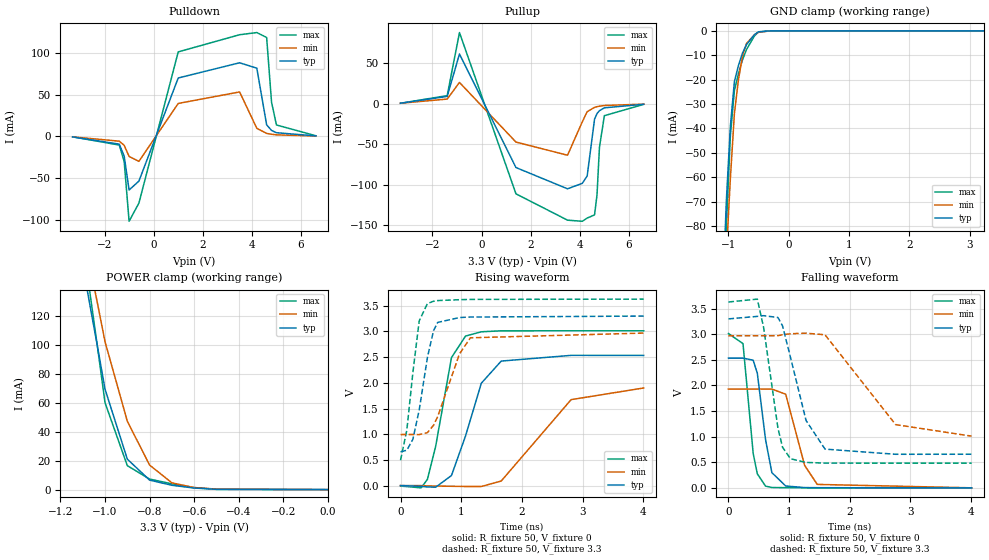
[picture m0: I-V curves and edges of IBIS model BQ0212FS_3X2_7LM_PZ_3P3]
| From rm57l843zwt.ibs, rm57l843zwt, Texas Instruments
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|   Model Cell FS_3X2_7LM_PZ_3P3
|BQ0212FS_3X2_7LM_PZ_3P3
[Model]   BQ0212FS_3X2_7LM_PZ_3P3
Model_type   I/O
Polarity   Non-Inverting
Enable   Active-Low
Vinl =  1.25
Vinh =  1.65
Cref =  15.0001pF
Rref =  101.0000M
Vref =  0V
Vmeas =  1.65
C_comp   1.2p   1.2p   1.2p
[Model Spec]
Vinl   1.25   1.12   1.38
Vinh   1.65   1.45   1.75
[Temperature Range]   25   155   -40
[Voltage Range]   3.3   2.97   3.63
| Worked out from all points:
|   slope of the pulldown table from 0 to 0.495 V, typ, clamps not added: 11.9 ohm
|   slope of the pullup table from 0 to 0.495 V, typ, clamps not added: 14.3 ohm
|   GND clamp passes 1 mA (typ) near -0.53 V on its own axis
|   POWER clamp passes 1 mA (typ) near -0.59 V on its own axis
|   rising waveform, R_fixture 50, V_fixture 0: 20-80 % time 399ps typ, 714ps min, 274ps max; typ from 0 V to 2.53 V
|   rising waveform, R_fixture 50, V_fixture 3.3: 20-80 % time 224ps typ, 347ps min, 171ps max; typ from 0.656 V to 3.3 V
|   falling waveform, R_fixture 50, V_fixture 0: 20-80 % time 170ps typ, 242ps min, 138ps max; typ from 2.53 V to 0 V
|   falling waveform, R_fixture 50, V_fixture 3.3: 20-80 % time 342ps typ, 655ps min, 230ps max; typ from 3.3 V to 0.657 V
[POWER_clamp]
|   voltage   I(typ)   I(min)   I(max)
-3.3V     2.375A     2.63A      3.153A
-1.1V     156mA      180.2mA    173.4mA
-1.067V   127.2mA    154.3mA    135.6mA
-1.033V   98.41mA    128.4mA    97.92mA
-1V       69.61mA    102.5mA    60.2mA
-900mV    21.12mA    47.41mA    16.6mA
-800mV    6.574mA    17mA       7.307mA
-700mV    2.998mA    4.687mA    3.989mA
-600mV    1.086mA    1.404mA    1.425mA
-500mV    187uA      358uA      203.4uA
0V        311.4pA    5.945nA    272.3pA
[Pulldown]
|   voltage   I(typ)   I(min)   I(max)
-3.3V     -554.3uA   -511.5uA   -526.2uA
-1.4V     -9.291mA   -5.703mA   -10.34mA
-1.2V     -23.68mA   -10.64mA   -30.19mA
-1V       -64.35mA   -24mA      -101.9mA
-600mV    -53.61mA   -29.92mA   -79.98mA
1V        70.16mA    39.6mA     101.5mA
3.5V      88.44mA    53.42mA    122.1mA
4.2V      81.93mA    9.711mA    124.7mA
4.6V      13.96mA    3.646mA    118.8mA
4.8V      7.183mA    2.57mA     41.14mA
5V        4.453mA    1.905mA    13.75mA
6.6V      621.1uA    479.2uA    840.9uA
[Pullup]
|   voltage   I(typ)   I(min)   I(max)
-3.3V     614.6uA    591.9uA    551.1uA
-1.4V     9.028mA    5.738mA    10.01mA
-900mV    61.32mA    26.24mA    87.8mA
1.4V      -78.76mA   -47.33mA   -111.2mA
3.5V      -105mA     -63.56mA   -143.7mA
4.1V      -98.29mA   -22.39mA   -145.1mA
4.3V      -89.13mA   -9.839mA   -141.1mA
4.6V      -19.02mA   -4.469mA   -137.2mA
4.7V      -12.15mA   -3.653mA   -112.5mA
4.8V      -8.616mA   -3.042mA   -53.65mA
5V        -5.089mA   -2.205mA   -14.76mA
6.6V      -663.5uA   -536.5uA   -825.6uA
[GND_clamp]
|   voltage   I(typ)   I(min)   I(max)
-3.3V     -1.947A    -1.623A    -3.254A
-1.1V     -112mA     -127mA     -135.8mA
-1.033V   -69.61mA   -91.63mA   -80.19mA
-966.7mV  -39.23mA   -60.62mA   -43.11mA
-900mV    -20.86mA   -34.02mA   -24.52mA
-833.3mV  -14.26mA   -20.12mA   -17.61mA
-766.7mV  -9.192mA   -10.52mA   -12mA
-700mV    -5.665mA   -5.207mA   -7.702mA
-566.7mV  -1.565mA   -1.572mA   -2.054mA
-500mV    -402.1uA   -585.5uA   -459.6uA
-300mV    -821.9nA   -7.168uA   -404.6nA
3.233V    296.5pA    4.008uA    206.9pA
[Ramp]
| variable   typ   min   max
dV/dt_f   1.632017/0.3487468n   1.217274/0.676831n   1.942304/0.2338723n
dV/dt_r   1.540068/0.4015431n   1.170106/0.7431858n   1.835653/0.2780119n
R_load = 50
[Rising Waveform]
R_fixture = 50
V_fixture = 0
V_fixture_min = 0
V_fixture_max = 0
|   time   V(typ)   V(min)   V(max)
0s        300.3uV    -965.4nV   -9.822mV
340ps     -15.63mV   -290.7uV   -44.89mV
444ps     -27.36mV   -6.964mV   122.8mV
580ps     -31.81mV   -9.755mV   768.7mV
840ps     195.6mV    -13.95mV   2.492V
1.072ns   967.2mV    -18.2mV    2.911V
1.332ns   1.993V     -18.33mV   2.994V
1.66ns    2.424V     88.3mV     3.013V
2.812ns   2.535V     1.673V     3.014V
4.008ns   2.534V     1.9V       3.014V
[Rising Waveform]
R_fixture = 50
V_fixture = 3.3
V_fixture_min = 2.97
V_fixture_max = 3.63
|   time   V(typ)   V(min)   V(max)
0s        656.3mV    993.4mV    492.9mV
104ps     688mV      993.4mV    1.08V
204ps     901.4mV    993.5mV    2.203V
308ps     1.471V     992.1mV    3.207V
444ps     2.499V     1.03V      3.544V
544ps     3.015V     1.174V     3.589V
612ps     3.176V     1.34V      3.602V
972ps     3.272V     2.564V     3.619V
1.152ns   3.281V     2.877V     3.625V
4.008ns   3.3V       2.969V     3.63V
[Falling Waveform]
R_fixture = 50
V_fixture = 0
V_fixture_min = 0
V_fixture_max = 0
|   time   V(typ)   V(min)   V(max)
0s        2.534V     1.93V      3.014V
240ps     2.534V     1.93V      2.817V
408ps     2.493V     1.93V      671.4mV
476ps     2.238V     1.93V      274.9mV
612ps     939.9mV    1.93V      33.62mV
716ps     297.4mV    1.93V      7.303mV
944ps     36.39mV    1.829V     3.346mV
1.256ns   5.523mV    438.6mV    1.066mV
1.464ns   3.167mV    67.28mV    658uV
4.008ns   97.17uV    784.4uV    -1.881uV
[Falling Waveform]
R_fixture = 50
V_fixture = 3.3
V_fixture_min = 2.97
V_fixture_max = 3.63
|   time   V(typ)   V(min)   V(max)
0s        3.3V       2.97V      3.63V
476ps     3.349V     2.97V      3.686V
580ps     3.363V     2.97V      3.131V
816ps     3.327V     2.972V     1.165V
892ps     3.162V     2.99V      792.4mV
1.024ns   2.543V     3.01V      567.5mV
1.28ns    1.314V     3.021V     497mV
1.592ns   756.9mV    2.99V      483.4mV
2.756ns   655.8mV    1.235V     482.5mV
4.008ns   656.6mV    1.01V      482.2mV
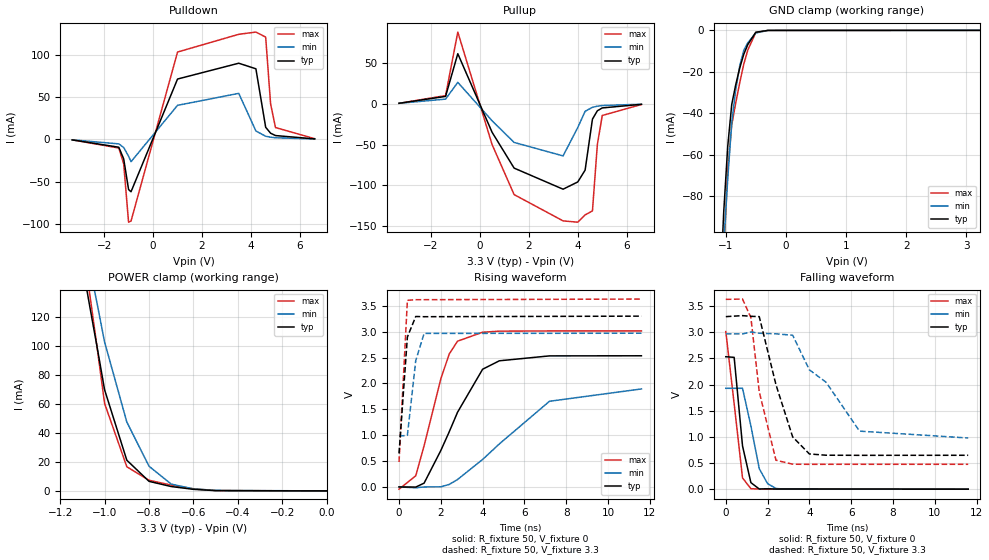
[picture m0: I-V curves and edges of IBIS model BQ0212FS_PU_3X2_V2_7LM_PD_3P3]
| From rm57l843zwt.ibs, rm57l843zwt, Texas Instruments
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|   Model Cell PD_3X2_V2_7LM_PD_3P3
|BQ0212FS_PU_3X2_V2_7LM_PD_3P3
[Model]   BQ0212FS_PU_3X2_V2_7LM_PD_3P3
Model_type   I/O
Polarity   Non-Inverting
Enable   Active-Low
Vinl =  1.25
Vinh =  1.65
Cref =  15.0001pF
Rref =  101.0000M
Vref =  0V
Vmeas =  1.65
C_comp   1.2p   1.2p   1.2p
[Model Spec]
Vinl   1.25   1.12   1.38
Vinh   1.65   1.45   1.75
[Temperature Range]   25   155   -40
[Voltage Range]   3.3   2.97   3.63
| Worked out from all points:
|   slope of the pulldown table from 0 to 0.495 V, typ, clamps not added: 11.8 ohm
|   slope of the pullup table from 0 to 0.495 V, typ, clamps not added: 14.3 ohm
|   GND clamp passes 1 mA (typ) near -0.50 V on its own axis
|   POWER clamp passes 1 mA (typ) near -0.59 V on its own axis
|   rising waveform, R_fixture 50, V_fixture 0: 20-80 % time 1.77ns typ, 3.13ns min, 1.22ns max; typ from 0 V to 2.53 V
|   rising waveform, R_fixture 50, V_fixture 3.3: 20-80 % time 283ps typ, 393ps min, 242ps max; typ from 0.648 V to 3.3 V
|   falling waveform, R_fixture 50, V_fixture 0: 20-80 % time 466ps typ, 594ps min, 516ps max; typ from 2.53 V to 0 V
|   falling waveform, R_fixture 50, V_fixture 3.3: 20-80 % time 1.14ns typ, 2.11ns min, 754ps max; typ from 3.3 V to 0.648 V
[POWER_clamp]
|   voltage   I(typ)   I(min)   I(max)
-3.3V     2.375A     2.63A      3.153A
-1.1V     156mA      180.2mA    173.4mA
-1.067V   127.2mA    154.3mA    135.7mA
-1.033V   98.42mA    128.4mA    97.94mA
-1V       69.62mA    102.5mA    60.22mA
-900mV    21.14mA    47.42mA    16.64mA
-800mV    6.593mA    17.01mA    7.345mA
-700mV    3.017mA    4.694mA    4.027mA
-600mV    1.106mA    1.412mA    1.463mA
-500mV    206.7uA    366.5uA    241.6uA
0V        19.75uA    8.576uA    38.26uA
[Pulldown]
|   voltage   I(typ)   I(min)   I(max)
-3.3V     -560.7uA   -504.5uA   -563.6uA
-1.4V     -9.199mA   -5.273mA   -10.11mA
-1.2V     -22.91mA   -9.491mA   -28.67mA
-1V       -59mA      -19.85mA   -97.49mA
-900mV    -61.64mA   -26.24mA   -96.13mA
1V        71.11mA    40.13mA    102.9mA
3.5V      89.74mA    54.24mA    123.8mA
4.2V      83.16mA    9.923mA    126.4mA
4.6V      14.26mA    3.714mA    120.5mA
4.8V      7.317mA    2.617mA    42.02mA
5V        4.531mA    1.939mA    13.99mA
6.6V      631.1uA    487.2uA    853.6uA
[Pullup]
|   voltage   I(typ)   I(min)   I(max)
-3.3V     614.6uA    591.9uA    551.1uA
-1.4V     9.028mA    5.738mA    10.01mA
-900mV    61.32mA    26.24mA    87.8mA
500mV     -34.85mA   -20.79mA   -49.88mA
1.4V      -78.76mA   -47.33mA   -111.2mA
3.4V      -104.6mA   -63.81mA   -143.4mA
4V        -95.71mA   -29.08mA   -145mA
4.3V      -81.25mA   -9.188mA   -136.1mA
4.6V      -18.8mA    -4.29mA    -131.2mA
4.8V      -8.576mA   -2.945mA   -49.93mA
5V        -5.064mA   -2.148mA   -14.33mA
6.6V      -672.1uA   -541.9uA   -866.9uA
[GND_clamp]
|   voltage   I(typ)   I(min)   I(max)
-3.3V     -1.951A    -1.627A    -3.261A
-1.1V     -130.1mA   -138.8mA   -166.7mA
-1.033V   -87.46mA   -103.2mA   -108mA
-966.7mV  -55.98mA   -71.78mA   -67.59mA
-900mV    -35.71mA   -44.42mA   -45.59mA
-833.3mV  -26.16mA   -28.61mA   -34.93mA
-766.7mV  -18.09mA   -17.01mA   -25.16mA
-700mV    -11.51mA   -9.612mA   -16.28mA
-633.3mV  -6.846mA   -5.983mA   -9.513mA
-500mV    -881.4uA   -1.246mA   -1.02mA
-300mV    -7.947uA   -18.83uA   -10.9uA
3.233V    19.75uA    12.58uA    38.26uA
[Ramp]
| variable   typ   min   max
dV/dt_f   1.620175/1.105022n   1.217177/2.126489n   1.924776/0.7617617n
dV/dt_r   1.544873/1.792143n   1.178612/3.281741n   1.835195/1.194097n
R_load = 50
[Rising Waveform]
R_fixture = 50
V_fixture = 0
V_fixture_min = 0
V_fixture_max = 0
|   time   V(typ)   V(min)   V(max)
0s        -78.38uV   106.6uV    -43.53mV
800ps     -3.412mV   -17.04mV   215.6mV
1.2ns     73.29mV    -1.069mV   797.2mV
2ns       703.8mV    2.209mV    2.088V
2.4ns     1.063V     47.73mV    2.567V
2.8ns     1.443V     142.5mV    2.816V
4ns       2.274V     530.6mV    2.989V
4.8ns     2.437V     830.6mV    3.01V
7.2ns     2.532V     1.655V     3.014V
11.6ns    2.534V     1.893V     3.014V
[Rising Waveform]
R_fixture = 50
V_fixture = 3.3
V_fixture_min = 2.97
V_fixture_max = 3.63
|   time   V(typ)   V(min)   V(max)
0s        648.2mV    982.1mV    482.6mV
400ps     2.898V     997.4mV    3.606V
800ps     3.293V     2.442V     3.618V
1.2ns     3.289V     2.966V     3.618V
11.6ns    3.3V       2.97V      3.63V
[Falling Waveform]
R_fixture = 50
V_fixture = 0
V_fixture_min = 0
V_fixture_max = 0
|   time   V(typ)   V(min)   V(max)
0s        2.533V     1.929V     3.014V
400ps     2.521V     1.929V     1.631V
800ps     826.9mV    1.929V     215.2mV
1.2ns     125.1mV    1.211V     9.278mV
1.6ns     3.329mV    392.5mV    2.376mV
2ns       6.783mV    105.2mV    3.1mV
2.4ns     2.585mV    13.28mV    1.346mV
2.8ns     3.784mV    1.115mV    365.3uV
11.6ns    24.58nV    30.81uV    -4.326uV
[Falling Waveform]
R_fixture = 50
V_fixture = 3.3
V_fixture_min = 2.97
V_fixture_max = 3.63
|   time   V(typ)   V(min)   V(max)
0s        3.3V       2.97V      3.63V
800ps     3.319V     2.969V     3.636V
1.2ns     3.306V     3.007V     3.283V
1.6ns     3.3V       2.983V     1.863V
2.4ns     1.998V     2.971V     553.7mV
3.2ns     999.2mV    2.944V     477.3mV
4ns       673.4mV    2.282V     474.8mV
4.8ns     649.3mV    2.045V     475.3mV
6.4ns     647.3mV    1.11V      475.5mV
11.6ns    648.1mV    978.7mV    475.5mV
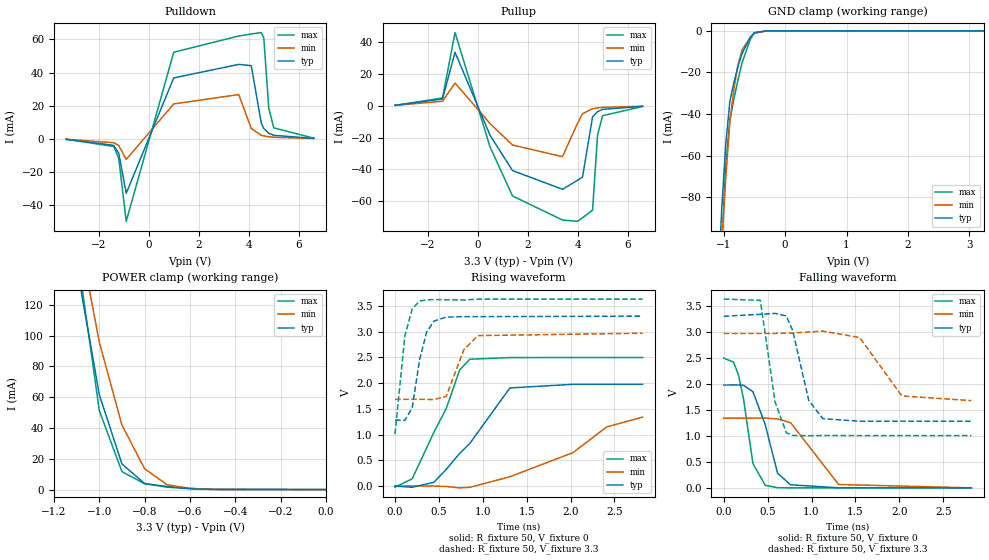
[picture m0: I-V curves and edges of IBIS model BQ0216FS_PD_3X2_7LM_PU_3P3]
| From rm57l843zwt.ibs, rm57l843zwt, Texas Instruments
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|   Model Cell FS_PD_3X2_7LM_PU_3P3
|BQ0216FS_PD_3X2_7LM_PU_3P3
[Model]   BQ0216FS_PD_3X2_7LM_PU_3P3
Model_type   I/O
Polarity   Non-Inverting
Enable   Active-Low
Vinl =  1.25
Vinh =  1.65
Cref =  15.0001pF
Rref =  101.0000M
Vref =  0V
Vmeas =  1.65
C_comp   1.2p   1.2p   1.2p
[Model Spec]
Vinl   1.25   1.12   1.38
Vinh   1.65   1.45   1.75
[Temperature Range]   25   155   -40
[Voltage Range]   3.3   2.97   3.63
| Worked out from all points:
|   slope of the pulldown table from 0 to 0.495 V, typ, clamps not added: 22 ohm
|   slope of the pullup table from 0 to 0.495 V, typ, clamps not added: 26.9 ohm
|   GND clamp passes 1 mA (typ) near -0.51 V on its own axis
|   POWER clamp passes 1 mA (typ) near -0.64 V on its own axis
|   rising waveform, R_fixture 50, V_fixture 0: 20-80 % time 523ps typ, 914ps min, 385ps max; typ from 0 V to 1.98 V
|   rising waveform, R_fixture 50, V_fixture 3.3: 20-80 % time 130ps typ, 167ps min, 107ps max; typ from 1.28 V to 3.3 V
|   falling waveform, R_fixture 50, V_fixture 0: 20-80 % time 181ps typ, 293ps min, 135ps max; typ from 1.98 V to 0 V
|   falling waveform, R_fixture 50, V_fixture 3.3: 20-80 % time 167ps typ, 275ps min, 128ps max; typ from 3.3 V to 1.28 V
[POWER_clamp]
|   voltage   I(typ)   I(min)   I(max)
-3.3V     2.372A     2.627A     3.149A
-1.1V     146.3mA    173.4mA    157.2mA
-1.067V   118.1mA    147.6mA    122mA
-1.033V   89.96mA    121.8mA    86.72mA
-1V       61.8mA     95.97mA    51.48mA
-900mV    16.69mA    41.94mA    11.67mA
-800mV    3.933mA    13.54mA    3.818mA
-700mV    1.568mA    3.091mA    2.047mA
-600mV    564.8uA    784.8uA    737.8uA
-500mV    103.9uA    192uA      116.2uA
0V        431.1pA    11.93nA    330.2pA
[Pulldown]
|   voltage   I(typ)   I(min)   I(max)
-3.3V     -267.3uA   -240.3uA   -277.5uA
-1.4V     -3.909mA   -2.325mA   -4.573mA
-1.2V     -8.625mA   -3.984mA   -11.65mA
-900mV    -32.84mA   -12.44mA   -49.75mA
1V        36.78mA    21.07mA    52.28mA
3.6V      44.94mA    26.74mA    62.08mA
4.1V      44.19mA    6.262mA    63.32mA
4.5V      9.589mA    2.146mA    64.15mA
4.6V      6.254mA    1.77mA     61.06mA
4.8V      3.393mA    1.259mA    18.58mA
5V        2.151mA    937.3uA    6.64mA
6.6V      305.4uA    234.7uA    420.4uA
[Pullup]
|   voltage   I(typ)   I(min)   I(max)
-3.3V     305.1uA    297.8uA    276.2uA
-1.4V     4.292mA    2.856mA    4.957mA
-900mV    33.76mA    14.39mA    46.19mA
500mV     -18.55mA   -11.22mA   -25.91mA
1.4V      -40.82mA   -24.72mA   -56.86mA
3.4V      -52.65mA   -32.06mA   -72.03mA
4V        -46.93mA   -10.94mA   -72.82mA
4.2V      -44.87mA   -4.98mA    -70.6mA
4.6V      -7.002mA   -1.879mA   -65.79mA
4.8V      -3.625mA   -1.322mA   -18.4mA
5V        -2.249mA   -979.1uA   -6.262mA
6.6V      -318.8uA   -256.1uA   -426.7uA
[GND_clamp]
|   voltage   I(typ)   I(min)   I(max)
-3.3V     -1.951A    -1.626A    -3.26A
-1.1V     -128.8mA   -138.1mA   -164.4mA
-1.033V   -85.86mA   -102.5mA   -105.1mA
-966.7mV  -54.21mA   -70.98mA   -64.57mA
-900mV    -33.86mA   -43.59mA   -42.8mA
-833.3mV  -24.67mA   -27.83mA   -32.66mA
-766.7mV  -16.98mA   -16.33mA   -23.45mA
-700mV    -10.78mA   -9.099mA   -15.18mA
-566.7mV  -3.09mA    -2.997mA   -4.136mA
-500mV    -830.4uA   -1.167mA   -966uA
-300mV    -21.18uA   -24.88uA   -33.63uA
3.233V    -1.13uA    4.967uA    -9.303uA
[Ramp]
| variable   typ   min   max
dV/dt_f   1.252541/0.1711906n  0.8046899/0.2807458n   1.627624/0.1305981n
dV/dt_r   1.216528/0.5378254n  0.8250621/0.9492667n   1.533176/0.3914158n
R_load = 50
[Rising Waveform]
R_fixture = 50
V_fixture = 0
V_fixture_min = 0
V_fixture_max = 0
|   time   V(typ)   V(min)   V(max)
0s        181.9uV    395.6uV    -22.89mV
196ps     -24.28mV   579.2uV    141.5mV
444ps     74.98mV    -148.8uV   1.046V
584ps     323.9mV    -8.283mV   1.508V
736ps     634mV      -34.85mV   2.253V
852ps     827.3mV    -24.92mV   2.463V
1.308ns   1.905V     180.4mV    2.495V
2.028ns   1.976V     649.7mV    2.496V
2.412ns   1.977V     1.149V     2.496V
2.82ns    1.977V     1.339V     2.496V
[Rising Waveform]
R_fixture = 50
V_fixture = 3.3
V_fixture_min = 2.97
V_fixture_max = 3.63
|   time   V(typ)   V(min)   V(max)
0s        1.282V     1.683V     1.011V
112ps     1.276V     1.683V     2.915V
196ps     1.521V     1.683V     3.441V
280ps     2.452V     1.683V     3.593V
360ps     2.989V     1.683V     3.616V
444ps     3.203V     1.679V     3.621V
584ps     3.281V     1.744V     3.618V
784ps     3.289V     2.645V     3.614V
944ps     3.29V      2.922V     3.63V
2.82ns    3.3V       2.968V     3.63V
[Falling Waveform]
R_fixture = 50
V_fixture = 0
V_fixture_min = 0
V_fixture_max = 0
|   time   V(typ)   V(min)   V(max)
0s        1.977V     1.34V      2.495V
112ps     1.98V      1.34V      2.418V
168ps     1.978V     1.34V      2.166V
224ps     1.974V     1.34V      1.719V
332ps     1.849V     1.341V     466.6mV
472ps     1.217V     1.343V     49.94mV
612ps     283.2mV    1.327V     3.653mV
760ps     59.68mV    1.255V     661.6uV
1.308ns   1.082mV    65.16mV    356.5uV
2.82ns    348.6uV    786.8uV    323.9uV
[Falling Waveform]
R_fixture = 50
V_fixture = 3.3
V_fixture_min = 2.97
V_fixture_max = 3.63
|   time   V(typ)   V(min)   V(max)
0s        3.3V       2.97V      3.63V
416ps     3.338V     2.97V      3.607V
584ps     3.356V     2.97V      1.653V
712ps     3.307V     2.975V     1.061V
784ps     3.029V     2.978V     1.008V
968ps     1.681V     2.999V     1.004V
1.128ns   1.332V     3.014V     1.007V
1.548ns   1.281V     2.891V     1.006V
2.028ns   1.283V     1.768V     1.006V
2.82ns    1.281V     1.678V     1.006V
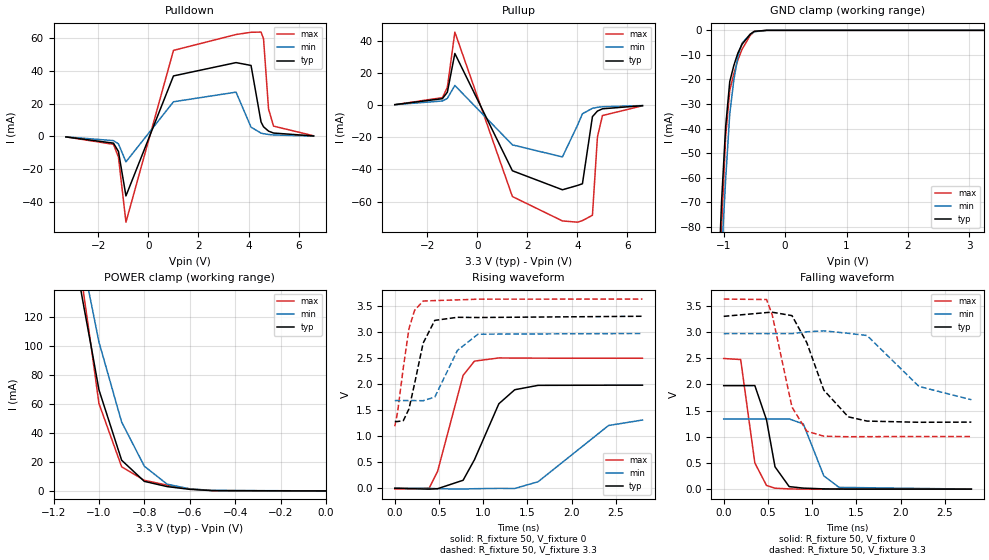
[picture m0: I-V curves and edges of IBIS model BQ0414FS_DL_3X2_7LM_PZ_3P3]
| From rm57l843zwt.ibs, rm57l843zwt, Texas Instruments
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|   Model Cell FS_DL_3X2_7LM_PZ_3P3
|BQ0414FS_DL_3X2_7LM_PZ_3P3
[Model]   BQ0414FS_DL_3X2_7LM_PZ_3P3
Model_type   I/O
Polarity   Non-Inverting
Enable   Active-Low
Vinl =  1.25
Vinh =  1.65
Cref =  15.0001pF
Rref =  101.0000M
Vref =  0V
Vmeas =  1.65
C_comp   1.2p   1.2p   1.2p
[Model Spec]
Vinl   1.25   1.12   1.38
Vinh   1.65   1.45   1.75
[Temperature Range]   25   155   -40
[Voltage Range]   3.3   2.97   3.63
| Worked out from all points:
|   slope of the pulldown table from 0 to 0.495 V, typ, clamps not added: 22 ohm
|   slope of the pullup table from 0 to 0.495 V, typ, clamps not added: 26.9 ohm
|   GND clamp passes 1 mA (typ) near -0.53 V on its own axis
|   POWER clamp passes 1 mA (typ) near -0.59 V on its own axis
|   rising waveform, R_fixture 50, V_fixture 0: 20-80 % time 302ps typ, 544ps min, 228ps max; typ from 0 V to 1.98 V
|   rising waveform, R_fixture 50, V_fixture 3.3: 20-80 % time 159ps typ, 218ps min, 123ps max; typ from 1.28 V to 3.3 V
|   falling waveform, R_fixture 50, V_fixture 0: 20-80 % time 127ps typ, 178ps min, 108ps max; typ from 1.98 V to 0 V
|   falling waveform, R_fixture 50, V_fixture 3.3: 20-80 % time 288ps typ, 444ps min, 206ps max; typ from 3.3 V to 1.28 V
[POWER_clamp]
|   voltage   I(typ)   I(min)   I(max)
-3.3V     2.375A     2.63A      3.153A
-1.1V     156mA      180.2mA    173.4mA
-1.067V   127.2mA    154.3mA    135.6mA
-1.033V   98.41mA    128.4mA    97.92mA
-1V       69.61mA    102.5mA    60.2mA
-900mV    21.13mA    47.41mA    16.61mA
-800mV    6.576mA    17mA       7.309mA
-700mV    2.999mA    4.688mA    3.99mA
-600mV    1.087mA    1.404mA    1.425mA
-500mV    187uA      358.1uA    203.4uA
0V        311.4pA    5.945nA    272.3pA
[Pulldown]
|   voltage   I(typ)   I(min)   I(max)
-3.3V     -269.8uA   -248.1uA   -260.2uA
-1.4V     -4.056mA   -2.548mA   -4.78mA
-1.2V     -9.104mA   -4.482mA   -12.53mA
-900mV    -36.12mA   -15.43mA   -52.08mA
1V        36.78mA    21.07mA    52.28mA
3.5V      44.86mA    26.92mA    61.93mA
4.1V      43.14mA    5.644mA    63.29mA
4.5V      8.805mA    2.025mA    63.4mA
4.6V      5.861mA    1.678mA    59.29mA
4.8V      3.241mA    1.203mA    16.69mA
5V        2.072mA    900.6uA    6.272mA
6.6V      302.2uA    232.4uA    414.2uA
[Pullup]
|   voltage   I(typ)   I(min)   I(max)
-3.3V     296.7uA    284.3uA    270.4uA
-1.4V     3.996mA    2.582mA    4.655mA
-1.2V     8.017mA    4.201mA    10.97mA
-900mV    32.15mA    12.24mA    45.44mA
1.4V      -40.82mA   -24.72mA   -56.86mA
3.4V      -52.65mA   -32.22mA   -72.03mA
4V        -49.98mA   -12.64mA   -72.82mA
4.2V      -48.91mA   -5.386mA   -71.83mA
4.6V      -7.16mA    -1.965mA   -68.52mA
4.8V      -3.684mA   -1.373mA   -19.8mA
5V        -2.282mA   -1.01mA    -6.487mA
6.6V      -316.6uA   -254.8uA   -401.1uA
[GND_clamp]
|   voltage   I(typ)   I(min)   I(max)
-3.3V     -1.947A    -1.623A    -3.254A
-1.1V     -112mA     -127mA     -135.8mA
-1.033V   -69.61mA   -91.63mA   -80.19mA
-966.7mV  -39.23mA   -60.62mA   -43.11mA
-900mV    -20.86mA   -34.02mA   -24.52mA
-833.3mV  -14.26mA   -20.12mA   -17.61mA
-766.7mV  -9.194mA   -10.52mA   -12.01mA
-700mV    -5.668mA   -5.208mA   -7.706mA
-566.7mV  -1.566mA   -1.573mA   -2.055mA
-500mV    -402.3uA   -585.8uA   -459.7uA
-300mV    -821.9nA   -7.17uA    -404.6nA
3.233V    296.6pA    4.008uA    206.9pA
[Ramp]
| variable   typ   min   max
dV/dt_f   1.262961/0.2956306n  0.8122509/0.4809054n   1.634803/0.2111757n
dV/dt_r   1.20419/0.3061992n   0.819654/0.5758191n   1.518518/0.229552n
R_load = 50
[Rising Waveform]
R_fixture = 50
V_fixture = 0
V_fixture_min = 0
V_fixture_max = 0
|   time   V(typ)   V(min)   V(max)
0s        -18.03uV   -3.004uV   -14.91mV
388ps     -18.32mV   -1.505mV   632.3uV
484ps     -9.138mV   -10.42mV   325.9mV
772ps     152.3mV    -16.67mV   2.165V
900ps     545.6mV    -9.607mV   2.439V
1.176ns   1.62V      -3.318mV   2.5V
1.356ns   1.89V      -5.481mV   2.498V
1.62ns    1.974V     124.5mV    2.496V
2.416ns   1.977V     1.203V     2.495V
2.8ns     1.977V     1.309V     2.495V
[Rising Waveform]
R_fixture = 50
V_fixture = 3.3
V_fixture_min = 2.97
V_fixture_max = 3.63
|   time   V(typ)   V(min)   V(max)
0s        1.281V     1.682V     1.189V
32ps      1.28V      1.682V     1.465V
96ps      1.296V     1.682V     2.312V
160ps     1.521V     1.682V     3.061V
224ps     2.01V      1.682V     3.414V
320ps     2.783V     1.679V     3.592V
452ps     3.221V     1.749V     3.601V
708ps     3.28V      2.644V     3.614V
940ps     3.276V     2.956V     3.628V
2.8ns     3.3V       2.969V     3.63V
[Falling Waveform]
R_fixture = 50
V_fixture = 0
V_fixture_min = 0
V_fixture_max = 0
|   time   V(typ)   V(min)   V(max)
0s        1.977V     1.34V      2.495V
192ps     1.977V     1.34V      2.475V
352ps     1.978V     1.34V      500.2mV
484ps     1.323V     1.34V      70.76mV
580ps     426.9mV    1.34V      18.13mV
740ps     48.82mV    1.341V     4.658mV
900ps     19.7mV     1.246V     983.4uV
1.132ns   5.355mV    253.4mV    -255uV
1.304ns   2.032mV    34.01mV    -144.9uV
2.8ns     114.8uV    459.8uV    6.297uV
[Falling Waveform]
R_fixture = 50
V_fixture = 3.3
V_fixture_min = 2.97
V_fixture_max = 3.63
|   time   V(typ)   V(min)   V(max)
0s        3.3V       2.97V      3.63V
484ps     3.372V     2.97V      3.621V
548ps     3.379V     2.97V      3.332V
772ps     3.314V     2.97V      1.567V
940ps     2.795V     3.005V     1.106V
1.132ns   1.891V     3.023V     1.011V
1.408ns   1.381V     2.976V     1.001V
1.62ns    1.3V       2.934V     1.003V
2.208ns   1.277V     1.961V     1.005V
2.8ns     1.28V      1.708V     1.005V
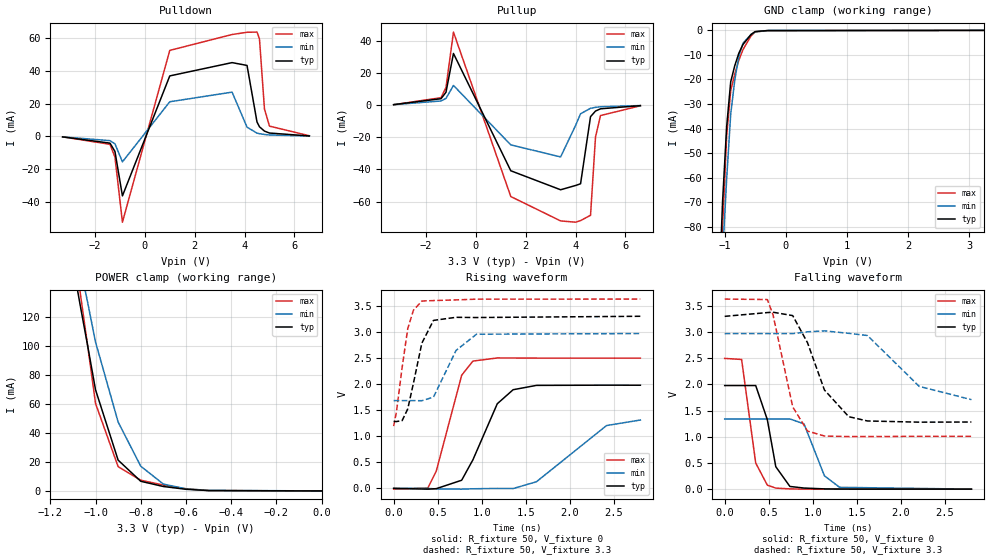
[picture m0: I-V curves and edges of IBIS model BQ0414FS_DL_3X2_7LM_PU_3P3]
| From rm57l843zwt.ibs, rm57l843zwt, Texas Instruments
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|   Model Cell FS_DL_3X2_7LM_PU_3P3
|BQ0414FS_DL_3X2_7LM_PU_3P3
[Model]   BQ0414FS_DL_3X2_7LM_PU_3P3
Model_type   I/O
Polarity   Non-Inverting
Enable   Active-Low
Vinl =  1.25
Vinh =  1.65
Cref =  15.0001pF
Rref =  101.0000M
Vref =  0V
Vmeas =  1.65
C_comp   1.2p   1.2p   1.2p
[Model Spec]
Vinl   1.25   1.12   1.38
Vinh   1.65   1.45   1.75
[Temperature Range]   25   155   -40
[Voltage Range]   3.3   2.97   3.63
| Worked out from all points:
|   slope of the pulldown table from 0 to 0.495 V, typ, clamps not added: 22 ohm
|   slope of the pullup table from 0 to 0.495 V, typ, clamps not added: 26.9 ohm
|   GND clamp passes 1 mA (typ) near -0.53 V on its own axis
|   POWER clamp passes 1 mA (typ) near -0.59 V on its own axis
|   rising waveform, R_fixture 50, V_fixture 0: 20-80 % time 303ps typ, 544ps min, 228ps max; typ from 0.001 V to 1.98 V
|   rising waveform, R_fixture 50, V_fixture 3.3: 20-80 % time 159ps typ, 218ps min, 123ps max; typ from 1.28 V to 3.3 V
|   falling waveform, R_fixture 50, V_fixture 0: 20-80 % time 127ps typ, 178ps min, 107ps max; typ from 1.98 V to 0.001 V
|   falling waveform, R_fixture 50, V_fixture 3.3: 20-80 % time 289ps typ, 444ps min, 206ps max; typ from 3.3 V to 1.28 V
[POWER_clamp]
|   voltage   I(typ)   I(min)   I(max)
-3.3V     2.375A     2.63A      3.153A
-1.1V     156mA      180.2mA    173.4mA
-1.067V   127.2mA    154.3mA    135.7mA
-1.033V   98.45mA    128.4mA    97.99mA
-1V       69.65mA    102.5mA    60.28mA
-900mV    21.19mA    47.43mA    16.7mA
-800mV    6.636mA    17.03mA    7.395mA
-700mV    3.052mA    4.718mA    4.065mA
-600mV    1.132mA    1.432mA    1.49mA
-500mV    224.9uA    381.2uA    256.9uA
0V        310pA      5.943nA    270.6pA
[Pulldown]
|   voltage   I(typ)   I(min)   I(max)
-3.3V     -269.8uA   -248.1uA   -260.2uA
-1.4V     -4.056mA   -2.548mA   -4.78mA
-1.2V     -9.105mA   -4.482mA   -12.53mA
-900mV    -36.12mA   -15.43mA   -52.09mA
1V        36.78mA    21.07mA    52.28mA
3.5V      44.86mA    26.92mA    61.93mA
4.1V      43.14mA    5.644mA    63.29mA
4.5V      8.805mA    2.025mA    63.4mA
4.6V      5.861mA    1.678mA    59.29mA
4.8V      3.241mA    1.203mA    16.69mA
5V        2.072mA    900.6uA    6.272mA
6.6V      302.2uA    232.4uA    414.2uA
[Pullup]
|   voltage   I(typ)   I(min)   I(max)
-3.3V     296.7uA    284.3uA    270.4uA
-1.4V     3.997mA    2.582mA    4.655mA
-1.2V     8.017mA    4.201mA    10.97mA
-900mV    32.15mA    12.24mA    45.44mA
1.4V      -40.82mA   -24.72mA   -56.86mA
3.4V      -52.65mA   -32.22mA   -72.03mA
4V        -49.98mA   -12.64mA   -72.82mA
4.2V      -48.91mA   -5.386mA   -71.83mA
4.6V      -7.16mA    -1.965mA   -68.53mA
4.8V      -3.684mA   -1.373mA   -19.8mA
5V        -2.282mA   -1.01mA    -6.487mA
6.6V      -316.6uA   -254.8uA   -401.1uA
[GND_clamp]
|   voltage   I(typ)   I(min)   I(max)
-3.3V     -1.947A    -1.623A    -3.254A
-1.1V     -112mA     -127.1mA   -135.8mA
-1.033V   -69.63mA   -91.64mA   -80.2mA
-966.7mV  -39.25mA   -60.63mA   -43.14mA
-900mV    -20.89mA   -34.03mA   -24.56mA
-833.3mV  -14.31mA   -20.14mA   -17.7mA
-766.7mV  -9.259mA   -10.54mA   -12.12mA
-700mV    -5.75mA    -5.239mA   -7.84mA
-566.7mV  -1.652mA   -1.618mA   -2.192mA
-500mV    -488.4uA   -632.2uA   -598.3uA
-300mV    -87.1uA    -54.14uA   -139.1uA
3.233V    -4.592uA   15.73uA    -37.4uA
[Ramp]
| variable   typ   min   max
dV/dt_f   1.261158/0.295917n   0.811193/0.4810727n   1.6326/0.2116804n
dV/dt_r   1.203622/0.3065388n  0.8196285/0.5759076n   1.51726/0.2296421n
R_load = 50
[Rising Waveform]
R_fixture = 50
V_fixture = 0
V_fixture_min = 0
V_fixture_max = 0
|   time   V(typ)   V(min)   V(max)
0s        1.159mV    959.5uV    -13.44mV
388ps     -14.61mV   -541.9uV   7.591mV
484ps     -4.995mV   -9.411mV   332.8mV
772ps     156.5mV    -14.8mV    2.169V
900ps     549.9mV    -7.397mV   2.441V
1.176ns   1.623V     -962.9uV   2.501V
1.356ns   1.892V     -3.133mV   2.5V
1.62ns    1.975V     126.9mV    2.498V
2.416ns   1.979V     1.205V     2.497V
2.8ns     1.978V     1.311V     2.497V
[Rising Waveform]
R_fixture = 50
V_fixture = 3.3
V_fixture_min = 2.97
V_fixture_max = 3.63
|   time   V(typ)   V(min)   V(max)
0s        1.284V     1.684V     1.193V
32ps      1.282V     1.684V     1.47V
96ps      1.299V     1.684V     2.317V
160ps     1.524V     1.684V     3.064V
224ps     2.013V     1.684V     3.415V
320ps     2.785V     1.681V     3.592V
452ps     3.221V     1.75V      3.601V
708ps     3.28V      2.645V     3.614V
940ps     3.276V     2.956V     3.628V
2.8ns     3.3V       2.969V     3.63V
[Falling Waveform]
R_fixture = 50
V_fixture = 0
V_fixture_min = 0
V_fixture_max = 0
|   time   V(typ)   V(min)   V(max)
0s        1.979V     1.341V     2.497V
192ps     1.979V     1.341V     2.477V
352ps     1.979V     1.341V     499.4mV
484ps     1.327V     1.341V     77.84mV
580ps     429.1mV    1.341V     21.27mV
740ps     53.21mV    1.342V     6.328mV
900ps     22.38mV    1.248V     2.393mV
1.132ns   6.615mV    255.6mV    1.103mV
1.304ns   3.258mV    36.25mV    1.205mV
2.8ns     1.292mV    1.425mV    1.376mV
[Falling Waveform]
R_fixture = 50
V_fixture = 3.3
V_fixture_min = 2.97
V_fixture_max = 3.63
|   time   V(typ)   V(min)   V(max)
0s        3.3V       2.97V      3.63V
484ps     3.372V     2.97V      3.621V
548ps     3.379V     2.97V      3.333V
772ps     3.314V     2.97V      1.572V
940ps     2.796V     3.005V     1.11V
1.132ns   1.894V     3.023V     1.015V
1.408ns   1.384V     2.976V     1.005V
1.62ns    1.303V     2.934V     1.006V
2.208ns   1.28V      1.963V     1.009V
2.8ns     1.283V     1.71V      1.009V
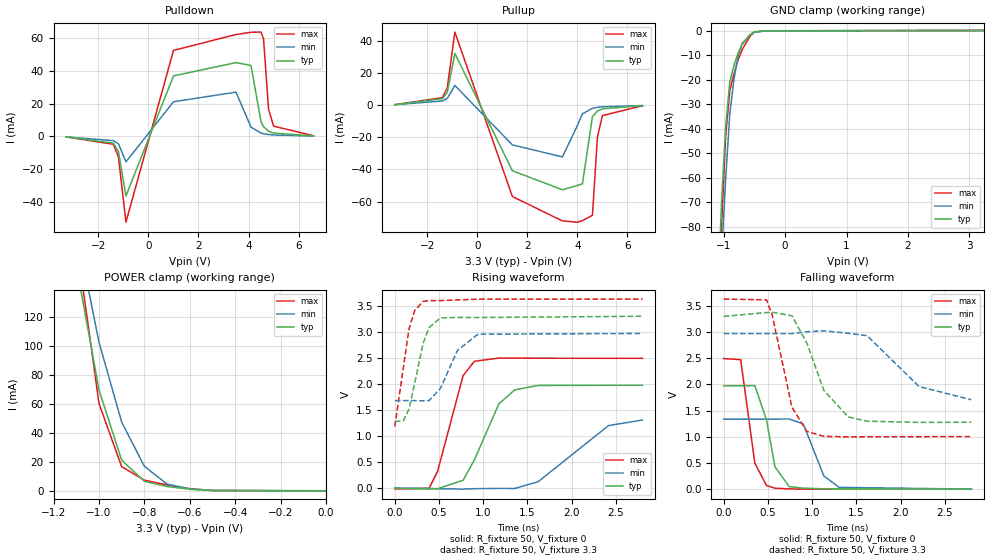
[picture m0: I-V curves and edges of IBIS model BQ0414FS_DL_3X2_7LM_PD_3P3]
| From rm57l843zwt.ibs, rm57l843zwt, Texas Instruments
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|   Model Cell FS_DL_3X2_7LM_PD_3P3
|BQ0414FS_DL_3X2_7LM_PD_3P3
[Model]   BQ0414FS_DL_3X2_7LM_PD_3P3
Model_type   I/O
Polarity   Non-Inverting
Enable   Active-Low
Vinl =  1.25
Vinh =  1.65
Cref =  15.0001pF
Rref =  101.0000M
Vref =  0V
Vmeas =  1.65
C_comp   1.2p   1.2p   1.2p
[Model Spec]
Vinl   1.25   1.12   1.38
Vinh   1.65   1.45   1.75
[Temperature Range]   25   155   -40
[Voltage Range]   3.3   2.97   3.63
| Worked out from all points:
|   slope of the pulldown table from 0 to 0.495 V, typ, clamps not added: 22 ohm
|   slope of the pullup table from 0 to 0.495 V, typ, clamps not added: 26.9 ohm
|   GND clamp passes 1 mA (typ) near -0.53 V on its own axis
|   POWER clamp passes 1 mA (typ) near -0.58 V on its own axis
|   rising waveform, R_fixture 50, V_fixture 0: 20-80 % time 302ps typ, 544ps min, 228ps max; typ from 0 V to 1.97 V
|   rising waveform, R_fixture 50, V_fixture 3.3: 20-80 % time 159ps typ, 218ps min, 124ps max; typ from 1.28 V to 3.3 V
|   falling waveform, R_fixture 50, V_fixture 0: 20-80 % time 127ps typ, 178ps min, 107ps max; typ from 1.97 V to 0 V
|   falling waveform, R_fixture 50, V_fixture 3.3: 20-80 % time 288ps typ, 444ps min, 206ps max; typ from 3.3 V to 1.28 V
[POWER_clamp]
|   voltage   I(typ)   I(min)   I(max)
-3.3V     2.375A     2.63A      3.153A
-1.1V     156mA      180.2mA    173.4mA
-1.067V   127.2mA    154.3mA    135.7mA
-1.033V   98.46mA    128.4mA    98.04mA
-1V       69.67mA    102.5mA    60.33mA
-900mV    21.21mA    47.43mA    16.77mA
-800mV    6.67mA     17.03mA    7.475mA
-700mV    3.094mA    4.728mA    4.157mA
-600mV    1.183mA    1.448mA    1.593mA
-500mV    283.5uA    402.1uA    371.9uA
0V        96.5uA     44.21uA    168.6uA
[Pulldown]
|   voltage   I(typ)   I(min)   I(max)
-3.3V     -269.8uA   -248.1uA   -260.2uA
-1.4V     -4.056mA   -2.548mA   -4.78mA
-1.2V     -9.105mA   -4.482mA   -12.53mA
-900mV    -36.12mA   -15.43mA   -52.09mA
1V        36.78mA    21.07mA    52.28mA
3.5V      44.86mA    26.92mA    61.93mA
4.1V      43.14mA    5.644mA    63.29mA
4.5V      8.805mA    2.025mA    63.4mA
4.6V      5.861mA    1.678mA    59.29mA
4.8V      3.241mA    1.203mA    16.69mA
5V        2.072mA    900.6uA    6.272mA
6.6V      302.2uA    232.4uA    414.2uA
[Pullup]
|   voltage   I(typ)   I(min)   I(max)
-3.3V     296.7uA    284.3uA    270.4uA
-1.4V     3.997mA    2.582mA    4.655mA
-1.2V     8.017mA    4.201mA    10.97mA
-900mV    32.15mA    12.24mA    45.44mA
1.4V      -40.82mA   -24.72mA   -56.86mA
3.4V      -52.65mA   -32.22mA   -72.03mA
4V        -49.98mA   -12.64mA   -72.82mA
4.2V      -48.91mA   -5.386mA   -71.82mA
4.6V      -7.16mA    -1.965mA   -68.53mA
4.8V      -3.684mA   -1.373mA   -19.8mA
5V        -2.282mA   -1.01mA    -6.487mA
6.6V      -316.6uA   -254.8uA   -401.1uA
[GND_clamp]
|   voltage   I(typ)   I(min)   I(max)
-3.3V     -1.947A    -1.623A    -3.254A
-1.1V     -112mA     -127.1mA   -135.8mA
-1.033V   -69.62mA   -91.64mA   -80.2mA
-966.7mV  -39.25mA   -60.63mA   -43.13mA
-900mV    -20.89mA   -34.03mA   -24.55mA
-833.3mV  -14.3mA    -20.13mA   -17.67mA
-766.7mV  -9.242mA   -10.53mA   -12.09mA
-700mV    -5.726mA   -5.229mA   -7.796mA
-566.7mV  -1.616mA   -1.599mA   -2.13mA
-500mV    -447.1uA   -610uA     -527.1uA
-300mV    -27.38uA   -21.6uA    -40.6uA
3.233V    96.49uA    48.22uA    168.5uA
[Ramp]
| variable   typ   min   max
dV/dt_f   1.262821/0.2955308n  0.8124759/0.4810597n   1.633828/0.2109792n
dV/dt_r   1.202664/0.3064033n  0.8187729/0.5761267n   1.516437/0.2299089n
R_load = 50
[Rising Waveform]
R_fixture = 50
V_fixture = 0
V_fixture_min = 0
V_fixture_max = 0
|   time   V(typ)   V(min)   V(max)
0s        -18.16uV   -3.064uV   -14.89mV
388ps     -18.24mV   -1.505mV   660.7uV
484ps     -9.085mV   -10.41mV   324.8mV
772ps     151.9mV    -16.63mV   2.16V
900ps     544.3mV    -9.58mV    2.435V
1.176ns   1.616V     -3.311mV   2.496V
1.356ns   1.887V     -5.472mV   2.495V
1.62ns    1.971V     124.3mV    2.493V
2.416ns   1.974V     1.201V     2.492V
2.8ns     1.974V     1.308V     2.492V
[Rising Waveform]
R_fixture = 50
V_fixture = 3.3
V_fixture_min = 2.97
V_fixture_max = 3.63
|   time   V(typ)   V(min)   V(max)
0s        1.278V     1.68V      1.185V
96ps      1.293V     1.68V      2.305V
160ps     1.517V     1.68V      3.053V
224ps     2.006V     1.68V      3.405V
320ps     2.779V     1.677V     3.583V
388ps     3.082V     1.68V      3.598V
516ps     3.267V     1.915V     3.598V
708ps     3.276V     2.642V     3.612V
940ps     3.274V     2.954V     3.626V
2.8ns     3.298V     2.968V     3.628V
[Falling Waveform]
R_fixture = 50
V_fixture = 0
V_fixture_min = 0
V_fixture_max = 0
|   time   V(typ)   V(min)   V(max)
0s        1.974V     1.338V     2.492V
192ps     1.974V     1.338V     2.471V
352ps     1.975V     1.338V     496.4mV
484ps     1.32V      1.338V     70.12mV
580ps     425.6mV    1.338V     18.22mV
740ps     48.56mV    1.339V     4.65mV
900ps     19.66mV    1.244V     995uV
1.132ns   5.337mV    252.8mV    -264.1uV
1.304ns   2.022mV    34mV       -146.2uV
2.8ns     112.2uV    448.5uV    5.492uV
[Falling Waveform]
R_fixture = 50
V_fixture = 3.3
V_fixture_min = 2.97
V_fixture_max = 3.63
|   time   V(typ)   V(min)   V(max)
0s        3.298V     2.969V     3.628V
484ps     3.37V      2.969V     3.613V
548ps     3.376V     2.969V     3.324V
772ps     3.309V     2.969V     1.561V
940ps     2.79V      3.004V     1.102V
1.132ns   1.886V     3.022V     1.008V
1.408ns   1.378V     2.974V     998.4mV
1.62ns    1.297V     2.931V     1V
2.208ns   1.274V     1.959V     1.002V
2.8ns     1.277V     1.706V     1.003V
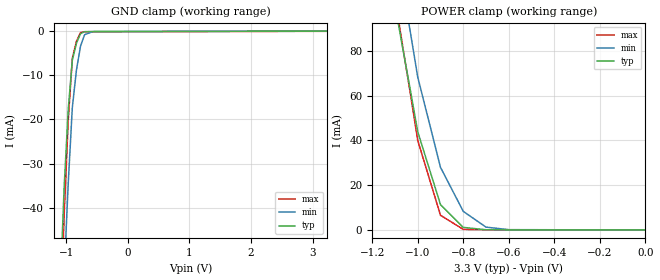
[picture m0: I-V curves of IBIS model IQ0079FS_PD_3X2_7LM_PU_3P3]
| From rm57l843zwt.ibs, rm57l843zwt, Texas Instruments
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|   Model Cell FS_PD_3X2_7LM_PU_3P3
|IQ0079FS_PD_3X2_7LM_PU_3P3
[Model]   IQ0079FS_PD_3X2_7LM_PU_3P3
Model_type   Input
Polarity   Non-Inverting
Vinl =  1.25
Vinh =  1.65
C_comp   1.2p   1.2p   1.2p
[Model Spec]
Vinl   1.25   1.12   1.38
Vinh   1.65   1.45   1.75
[Temperature Range]   25   155   -40
[Voltage Range]   3.3   2.97   3.63
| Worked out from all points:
|   GND clamp passes 1 mA (typ) near -0.78 V on its own axis
|   POWER clamp passes 1 mA (typ) near -0.79 V on its own axis
[POWER_clamp]
|   voltage   I(typ)   I(min)   I(max)
-3.3V     1.823A     2.351A     1.96A
-1.1V     100.7mA    129.7mA    104mA
-1.067V   81.78mA    109.2mA    82.67mA
-1.033V   62.85mA    88.78mA    61.35mA
-1V       43.91mA    68.32mA    40.03mA
-900mV    11.33mA    27.98mA    6.575mA
-800mV    1.159mA    8.31mA     262.7uA
-700mV    89.5uA     1.262mA    78.79uA
-600mV    47.29uA    138.9uA    65.15uA
0V        173.5pA    245.5pA    190.9pA
[GND_clamp]
|   voltage   I(typ)   I(min)   I(max)
-3.3V     -1.38A     -1.323A    -2.074A
-1.1V     -59.6mA    -79.12mA   -70.72mA
-1.033V   -35.5mA    -55.25mA   -41.84mA
-966.7mV  -17.83mA   -34.66mA   -20.32mA
-900mV    -6.605mA   -17.33mA   -6.158mA
-833.3mV  -2.754mA   -8.869mA   -2.319mA
-766.7mV  -592uA     -3.357mA   -314.7uA
-700mV    -119.5uA   -797.1uA   -143.3uA
-566.7mV  -87.28uA   -106.7uA   -139uA
3.233V    -4.592uA   11.77uA    -37.4uA
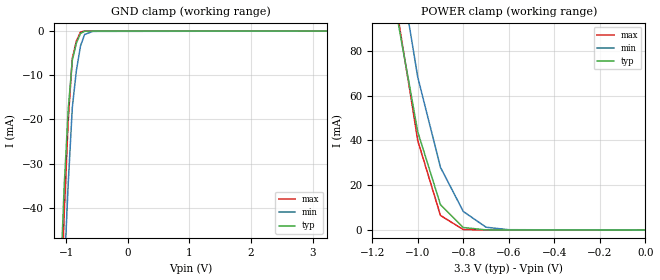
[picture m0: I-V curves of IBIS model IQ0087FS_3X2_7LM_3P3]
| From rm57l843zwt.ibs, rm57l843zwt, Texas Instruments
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|   Model Cell IQ0087FS_3X2_7LM_3P3
|IQ0087FS_3X2_7LM_3P3
[Model]   IQ0087FS_3X2_7LM_3P3
Model_type   Input
Polarity   Non-Inverting
Vinl =  1.25
Vinh =  1.65
C_comp   1.2p   1.2p   1.2p
[Model Spec]
Vinl   1.25   1.12   1.38
Vinh   1.65   1.45   1.75
[Temperature Range]   25   155   -40
[Voltage Range]   3.3   2.97   3.63
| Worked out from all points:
|   GND clamp passes 1 mA (typ) near -0.78 V on its own axis
|   POWER clamp passes 1 mA (typ) near -0.79 V on its own axis
[POWER_clamp]
|   voltage   I(typ)   I(min)   I(max)
-3.3V     1.823A     2.351A     1.96A
-1.1V     100.7mA    129.7mA    103.9mA
-1.067V   81.76mA    109.2mA    82.61mA
-1.033V   62.81mA    88.77mA    61.28mA
-1V       43.87mA    68.31mA    39.95mA
-900mV    11.27mA    27.96mA    6.481mA
-800mV    1.099mA    8.283mA    176.7uA
-700mV    35.91uA    1.232mA    3.424uA
-600mV    1.374uA    111.2uA    455.2nA
0V        175pA      247.2pA    192.5pA
[GND_clamp]
|   voltage   I(typ)   I(min)   I(max)
-3.3V     -1.38A     -1.323A    -2.074A
-1.1V     -59.59mA   -79.11mA   -70.71mA
-1.033V   -35.48mA   -55.25mA   -41.82mA
-966.7mV  -17.81mA   -34.65mA   -20.29mA
-900mV    -6.579mA   -17.32mA   -6.122mA
-833.3mV  -2.708mA   -8.853mA   -2.234mA
-766.7mV  -527.2uA   -3.335mA   -196uA
-700mV    -37.17uA   -765.8uA   -8.209uA
-566.7mV  -1.613uA   -62.15uA   -984.8nA
3.233V    169pA      53.88nA    156.8pA
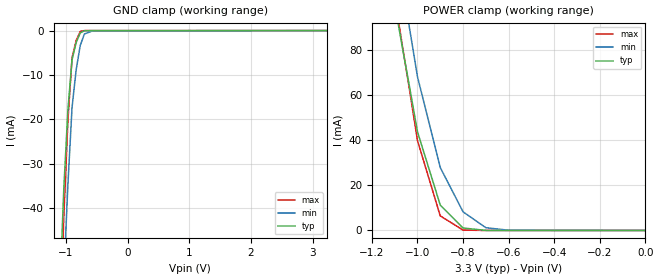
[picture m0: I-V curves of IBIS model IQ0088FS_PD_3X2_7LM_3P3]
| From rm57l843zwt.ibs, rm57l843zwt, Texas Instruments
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|   Model Cell 088FS_PD_3X2_7LM_3P3
|IQ0088FS_PD_3X2_7LM_3P3
[Model]   IQ0088FS_PD_3X2_7LM_3P3
Model_type   Input
Polarity   Non-Inverting
Vinl =  1.25
Vinh =  1.65
C_comp   1.2p   1.2p   1.2p
[Model Spec]
Vinl   1.25   1.12   1.38
Vinh   1.65   1.45   1.75
[Temperature Range]   25   155   -40
[Voltage Range]   3.3   2.97   3.63
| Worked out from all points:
|   GND clamp passes 1 mA (typ) near -0.78 V on its own axis
|   POWER clamp passes 1 mA (typ) near -0.79 V on its own axis
[POWER_clamp]
|   voltage   I(typ)   I(min)   I(max)
-3.3V     1.823A     2.351A     1.96A
-1.1V     100.7mA    129.7mA    103.9mA
-1.067V   81.75mA    109.2mA    82.61mA
-1.033V   62.81mA    88.77mA    61.28mA
-1V       43.87mA    68.31mA    39.95mA
-900mV    11.27mA    27.96mA    6.478mA
-800mV    1.097mA    8.282mA    174.3uA
-700mV    34.84uA    1.231mA    2.13uA
-600mV    1.042uA    110.9uA    105nA
0V        175pA      246.9pA    192.5pA
[GND_clamp]
|   voltage   I(typ)   I(min)   I(max)
-3.3V     -1.38A     -1.323A    -2.074A
-1.1V     -59.59mA   -79.11mA   -70.71mA
-1.033V   -35.48mA   -55.24mA   -41.82mA
-966.7mV  -17.81mA   -34.65mA   -20.29mA
-900mV    -6.577mA   -17.32mA   -6.12mA
-833.3mV  -2.706mA   -8.852mA   -2.231mA
-766.7mV  -524.8uA   -3.334mA   -192uA
-700mV    -34.57uA   -764.5uA   -4.564uA
-566.7mV  -912.9nA   -61.46uA   -232.6nA
3.233V    169pA      53.36nA    156.8pA
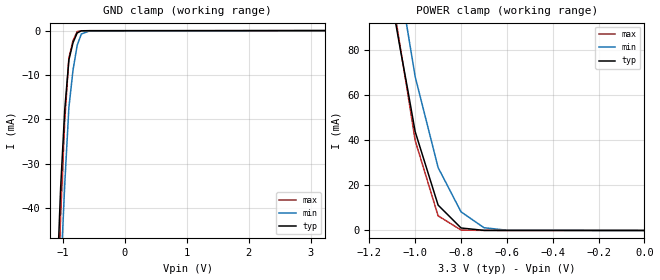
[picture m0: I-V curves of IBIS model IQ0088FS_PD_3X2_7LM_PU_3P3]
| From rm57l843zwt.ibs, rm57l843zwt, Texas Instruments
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|   Model Cell FS_PD_3X2_7LM_PU_3P3
|IQ0088FS_PD_3X2_7LM_PU_3P3
[Model]   IQ0088FS_PD_3X2_7LM_PU_3P3
Model_type   Input
Polarity   Non-Inverting
Vinl =  1.25
Vinh =  1.65
C_comp   1.2p   1.2p   1.2p
[Model Spec]
Vinl   1.25   1.12   1.38
Vinh   1.65   1.45   1.75
[Temperature Range]   25   155   -40
[Voltage Range]   3.3   2.97   3.63
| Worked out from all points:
|   GND clamp passes 1 mA (typ) near -0.78 V on its own axis
|   POWER clamp passes 1 mA (typ) near -0.79 V on its own axis
[POWER_clamp]
|   voltage   I(typ)   I(min)   I(max)
-3.3V     1.823A     2.351A     1.96A
-1.1V     100.7mA    129.7mA    103.9mA
-1.067V   81.76mA    109.2mA    82.62mA
-1.033V   62.82mA    88.77mA    61.29mA
-1V       43.88mA    68.31mA    39.96mA
-900mV    11.28mA    27.96mA    6.502mA
-800mV    1.112mA    8.288mA    196.7uA
-700mV    48.56uA    1.238mA    21.76uA
-600mV    12.73uA    117.7uA    16.83uA
0V        174.6pA    246.4pA    192.1pA
[GND_clamp]
|   voltage   I(typ)   I(min)   I(max)
-3.3V     -1.38A     -1.323A    -2.074A
-1.1V     -59.59mA   -79.11mA   -70.71mA
-1.033V   -35.48mA   -55.25mA   -41.82mA
-966.7mV  -17.81mA   -34.65mA   -20.3mA
-900mV    -6.582mA   -17.32mA   -6.126mA
-833.3mV  -2.714mA   -8.855mA   -2.246mA
-766.7mV  -537.7uA   -3.338mA   -216.9uA
-700mV    -53.02uA   -770.5uA   -36.99uA
-566.7mV  -20.37uA   -71.01uA   -32.99uA
3.233V    -1.13uA    2.97uA     -9.304uA
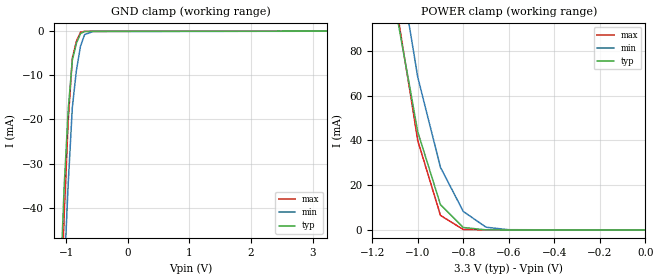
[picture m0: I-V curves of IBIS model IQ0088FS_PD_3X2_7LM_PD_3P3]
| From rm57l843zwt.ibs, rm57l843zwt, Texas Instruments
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|   Model Cell FS_PD_3X2_7LM_PD_3P3
|IQ0088FS_PD_3X2_7LM_PD_3P3
[Model]   IQ0088FS_PD_3X2_7LM_PD_3P3
Model_type   Input
Polarity   Non-Inverting
Vinl =  1.25
Vinh =  1.65
C_comp   1.2p   1.2p   1.2p
[Model Spec]
Vinl   1.25   1.12   1.38
Vinh   1.65   1.45   1.75
[Temperature Range]   25   155   -40
[Voltage Range]   3.3   2.97   3.63
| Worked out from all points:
|   GND clamp passes 1 mA (typ) near -0.78 V on its own axis
|   POWER clamp passes 1 mA (typ) near -0.79 V on its own axis
[POWER_clamp]
|   voltage   I(typ)   I(min)   I(max)
-3.3V     1.823A     2.351A     1.96A
-1.1V     100.7mA    129.7mA    104mA
-1.067V   81.76mA    109.2mA    82.62mA
-1.033V   62.82mA    88.77mA    61.3mA
-1V       43.88mA    68.31mA    39.97mA
-900mV    11.28mA    27.96mA    6.514mA
-800mV    1.116mA    8.288mA    212.3uA
-700mV    54.5uA     1.239mA    40.3uA
-600mV    20.76uA    119.2uA    38.33uA
0V        19.75uA    8.564uA    38.26uA
[GND_clamp]
|   voltage   I(typ)   I(min)   I(max)
-3.3V     -1.38A     -1.323A    -2.074A
-1.1V     -59.59mA   -79.11mA   -70.71mA
-1.033V   -35.48mA   -55.25mA   -41.82mA
-966.7mV  -17.81mA   -34.65mA   -20.3mA
-900mV    -6.581mA   -17.32mA   -6.125mA
-833.3mV  -2.713mA   -8.854mA   -2.244mA
-766.7mV  -535.2uA   -3.337mA   -211.5uA
-700mV    -48.7uA    -768.6uA   -28.52uA
-566.7mV  -12.98uA   -67.04uA   -19.79uA
3.233V    19.75uA    8.617uA    38.26uA
